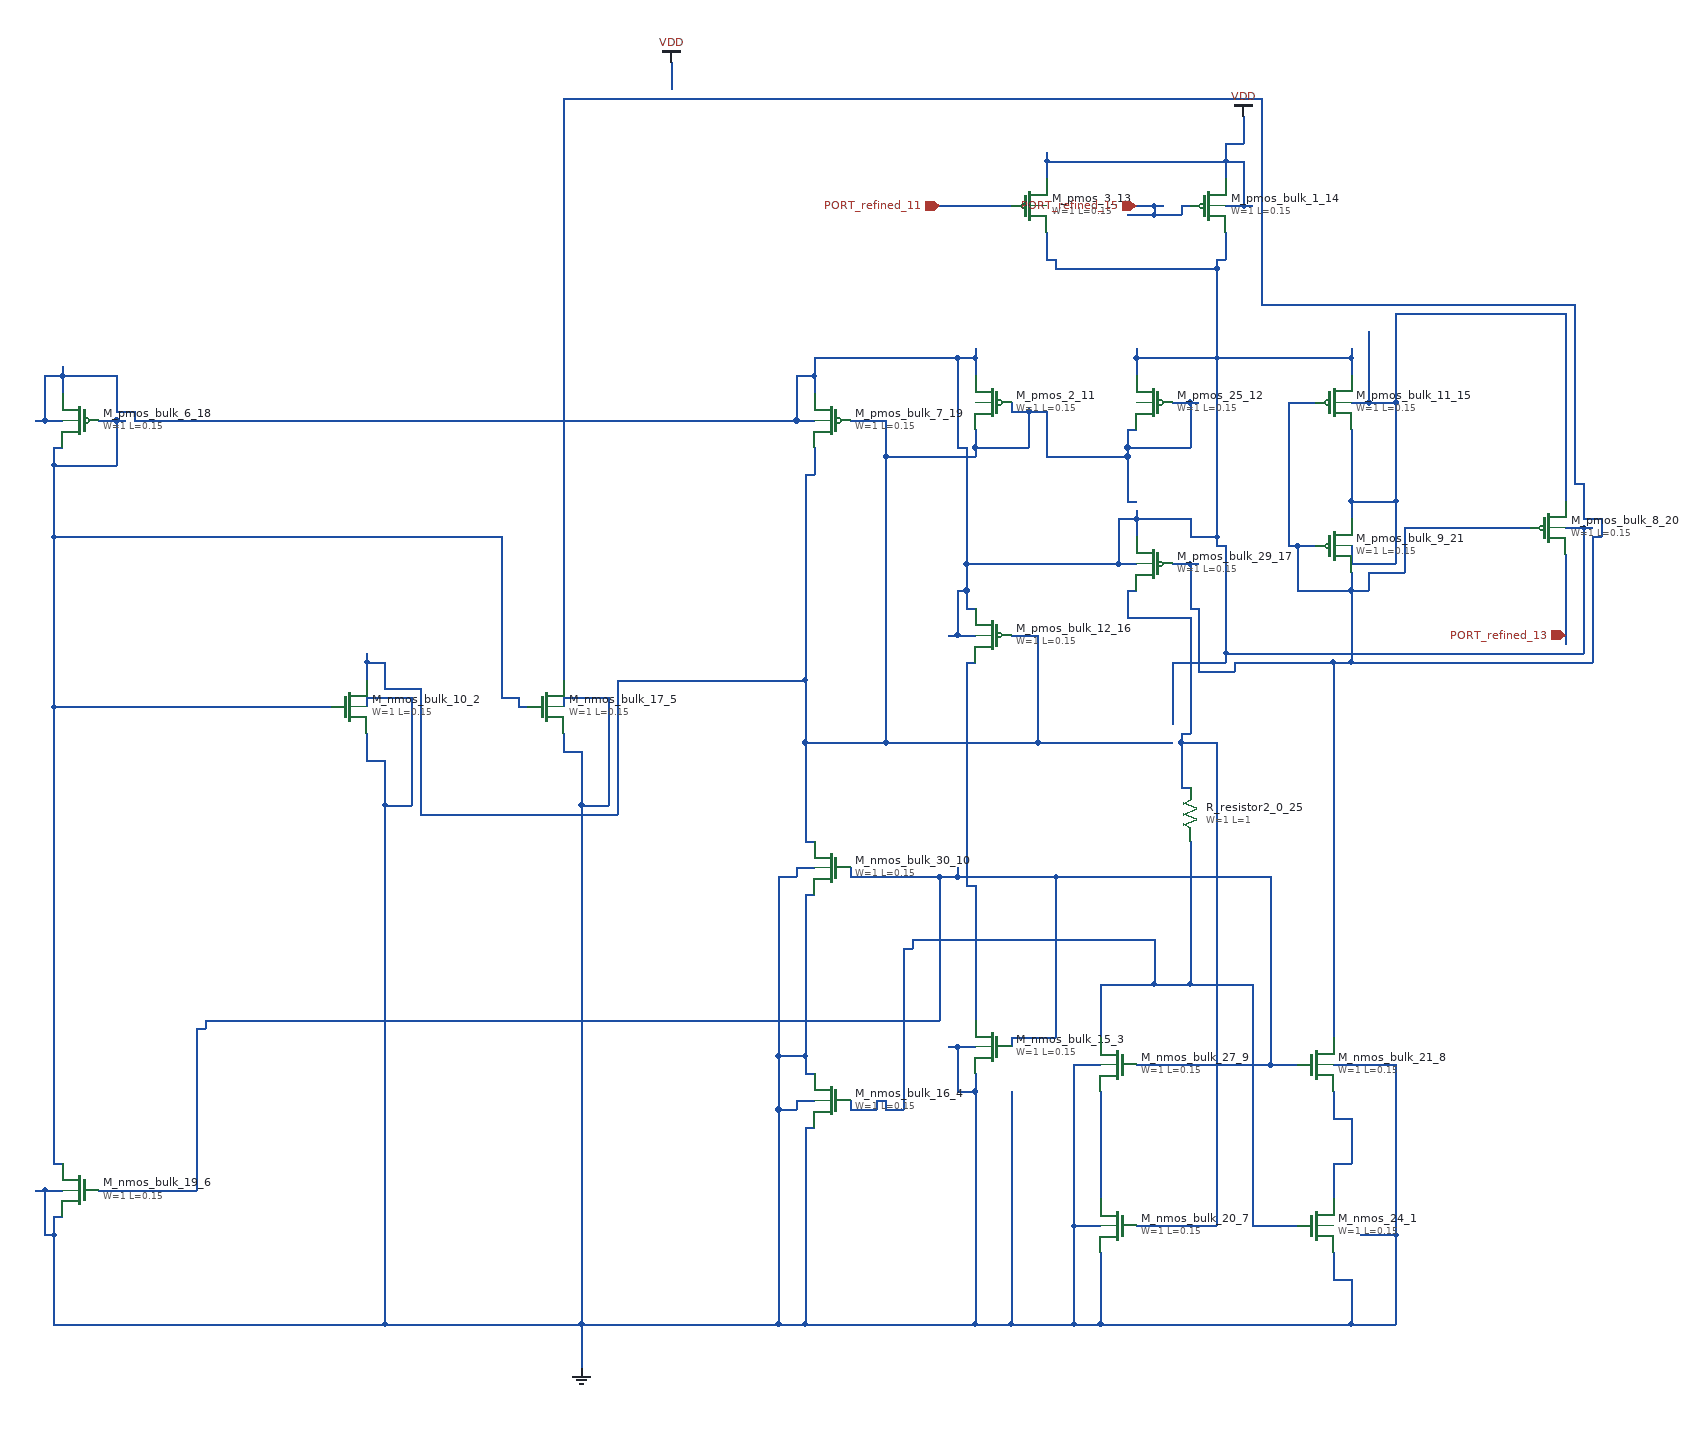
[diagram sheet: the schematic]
v {xschem version=3.4.8 file_version=1.2}
G {}
K {}
V {}
S {}
E {}
C {devices/gnd.sym} 800 1540 0 0 {name="l_gnd_5_0" lab="GND"}
C {sky130_fd_pr/nfet3_01v8.sym} 1620 1380 0 0 {name="M_nmos_24_1"
W=1
L=0.15
body=GND
nf=1
mult=1
ad="expr('int((@nf + 1)/2) * @W / @nf * 0.29')"
pd="expr('2*int((@nf + 1)/2) * (@W / @nf + 0.29)')"
as="expr('int((@nf + 2)/2) * @W / @nf * 0.29')"
ps="expr('2*int((@nf + 2)/2) * (@W / @nf + 0.29)')"
nrd="expr('0.29 / @W ')" nrs="expr('0.29 / @W ')"
sa=0 sb=0 sd=0
model=nfet_01v8
spiceprefix=X
}
C {sky130_fd_pr/nfet_01v8.sym} 540 800 0 0 {name="M_nmos_bulk_10_2"
W=1
L=0.15
nf=1 
mult=1
ad="expr('int((@nf + 1)/2) * @W / @nf * 0.29')"
pd="expr('2*int((@nf + 1)/2) * (@W / @nf + 0.29)')"
as="expr('int((@nf + 2)/2) * @W / @nf * 0.29')"
ps="expr('2*int((@nf + 2)/2) * (@W / @nf + 0.29)')"
nrd="expr('0.29 / @W ')" nrs="expr('0.29 / @W ')"
sa=0 sb=0 sd=0
model=nfet_01v8
spiceprefix=X
}
C {sky130_fd_pr/nfet_01v8.sym} 1260 1180 0 1 {name="M_nmos_bulk_15_3"
W=1
L=0.15
nf=1 
mult=1
ad="expr('int((@nf + 1)/2) * @W / @nf * 0.29')"
pd="expr('2*int((@nf + 1)/2) * (@W / @nf + 0.29)')"
as="expr('int((@nf + 2)/2) * @W / @nf * 0.29')"
ps="expr('2*int((@nf + 2)/2) * (@W / @nf + 0.29)')"
nrd="expr('0.29 / @W ')" nrs="expr('0.29 / @W ')"
sa=0 sb=0 sd=0
model=nfet_01v8
spiceprefix=X
}
C {sky130_fd_pr/nfet_01v8.sym} 1080 1240 0 1 {name="M_nmos_bulk_16_4"
W=1
L=0.15
nf=1 
mult=1
ad="expr('int((@nf + 1)/2) * @W / @nf * 0.29')"
pd="expr('2*int((@nf + 1)/2) * (@W / @nf + 0.29)')"
as="expr('int((@nf + 2)/2) * @W / @nf * 0.29')"
ps="expr('2*int((@nf + 2)/2) * (@W / @nf + 0.29)')"
nrd="expr('0.29 / @W ')" nrs="expr('0.29 / @W ')"
sa=0 sb=0 sd=0
model=nfet_01v8
spiceprefix=X
}
C {sky130_fd_pr/nfet_01v8.sym} 760 800 0 0 {name="M_nmos_bulk_17_5"
W=1
L=0.15
nf=1 
mult=1
ad="expr('int((@nf + 1)/2) * @W / @nf * 0.29')"
pd="expr('2*int((@nf + 1)/2) * (@W / @nf + 0.29)')"
as="expr('int((@nf + 2)/2) * @W / @nf * 0.29')"
ps="expr('2*int((@nf + 2)/2) * (@W / @nf + 0.29)')"
nrd="expr('0.29 / @W ')" nrs="expr('0.29 / @W ')"
sa=0 sb=0 sd=0
model=nfet_01v8
spiceprefix=X
}
C {sky130_fd_pr/nfet_01v8.sym} 240 1340 0 1 {name="M_nmos_bulk_19_6"
W=1
L=0.15
nf=1 
mult=1
ad="expr('int((@nf + 1)/2) * @W / @nf * 0.29')"
pd="expr('2*int((@nf + 1)/2) * (@W / @nf + 0.29)')"
as="expr('int((@nf + 2)/2) * @W / @nf * 0.29')"
ps="expr('2*int((@nf + 2)/2) * (@W / @nf + 0.29)')"
nrd="expr('0.29 / @W ')" nrs="expr('0.29 / @W ')"
sa=0 sb=0 sd=0
model=nfet_01v8
spiceprefix=X
}
C {sky130_fd_pr/nfet_01v8.sym} 1400 1380 0 1 {name="M_nmos_bulk_20_7"
W=1
L=0.15
nf=1 
mult=1
ad="expr('int((@nf + 1)/2) * @W / @nf * 0.29')"
pd="expr('2*int((@nf + 1)/2) * (@W / @nf + 0.29)')"
as="expr('int((@nf + 2)/2) * @W / @nf * 0.29')"
ps="expr('2*int((@nf + 2)/2) * (@W / @nf + 0.29)')"
nrd="expr('0.29 / @W ')" nrs="expr('0.29 / @W ')"
sa=0 sb=0 sd=0
model=nfet_01v8
spiceprefix=X
}
C {sky130_fd_pr/nfet_01v8.sym} 1620 1200 0 0 {name="M_nmos_bulk_21_8"
W=1
L=0.15
nf=1 
mult=1
ad="expr('int((@nf + 1)/2) * @W / @nf * 0.29')"
pd="expr('2*int((@nf + 1)/2) * (@W / @nf + 0.29)')"
as="expr('int((@nf + 2)/2) * @W / @nf * 0.29')"
ps="expr('2*int((@nf + 2)/2) * (@W / @nf + 0.29)')"
nrd="expr('0.29 / @W ')" nrs="expr('0.29 / @W ')"
sa=0 sb=0 sd=0
model=nfet_01v8
spiceprefix=X
}
C {sky130_fd_pr/nfet_01v8.sym} 1400 1200 0 1 {name="M_nmos_bulk_27_9"
W=1
L=0.15
nf=1 
mult=1
ad="expr('int((@nf + 1)/2) * @W / @nf * 0.29')"
pd="expr('2*int((@nf + 1)/2) * (@W / @nf + 0.29)')"
as="expr('int((@nf + 2)/2) * @W / @nf * 0.29')"
ps="expr('2*int((@nf + 2)/2) * (@W / @nf + 0.29)')"
nrd="expr('0.29 / @W ')" nrs="expr('0.29 / @W ')"
sa=0 sb=0 sd=0
model=nfet_01v8
spiceprefix=X
}
C {sky130_fd_pr/nfet_01v8.sym} 1080 980 0 1 {name="M_nmos_bulk_30_10"
W=1
L=0.15
nf=1 
mult=1
ad="expr('int((@nf + 1)/2) * @W / @nf * 0.29')"
pd="expr('2*int((@nf + 1)/2) * (@W / @nf + 0.29)')"
as="expr('int((@nf + 2)/2) * @W / @nf * 0.29')"
ps="expr('2*int((@nf + 2)/2) * (@W / @nf + 0.29)')"
nrd="expr('0.29 / @W ')" nrs="expr('0.29 / @W ')"
sa=0 sb=0 sd=0
model=nfet_01v8
spiceprefix=X
}
C {sky130_fd_pr/pfet3_01v8.sym} 1260 460 0 1 {name="M_pmos_2_11"
W=1
L=0.15
body=VDD
nf=1
mult=1
ad="expr('int((@nf + 1)/2) * @W / @nf * 0.29')"
pd="expr('2*int((@nf + 1)/2) * (@W / @nf + 0.29)')"
as="expr('int((@nf + 2)/2) * @W / @nf * 0.29')"
ps="expr('2*int((@nf + 2)/2) * (@W / @nf + 0.29)')"
nrd="expr('0.29 / @W ')" nrs="expr('0.29 / @W ')"
sa=0 sb=0 sd=0
model=pfet_01v8
spiceprefix=X
}
C {sky130_fd_pr/pfet3_01v8.sym} 1440 460 0 1 {name="M_pmos_25_12"
W=1
L=0.15
body=VDD
nf=1
mult=1
ad="expr('int((@nf + 1)/2) * @W / @nf * 0.29')"
pd="expr('2*int((@nf + 1)/2) * (@W / @nf + 0.29)')"
as="expr('int((@nf + 2)/2) * @W / @nf * 0.29')"
ps="expr('2*int((@nf + 2)/2) * (@W / @nf + 0.29)')"
nrd="expr('0.29 / @W ')" nrs="expr('0.29 / @W ')"
sa=0 sb=0 sd=0
model=pfet_01v8
spiceprefix=X
}
C {sky130_fd_pr/pfet3_01v8.sym} 1300 240 0 0 {name="M_pmos_3_13"
W=1
L=0.15
body=VDD
nf=1
mult=1
ad="expr('int((@nf + 1)/2) * @W / @nf * 0.29')"
pd="expr('2*int((@nf + 1)/2) * (@W / @nf + 0.29)')"
as="expr('int((@nf + 2)/2) * @W / @nf * 0.29')"
ps="expr('2*int((@nf + 2)/2) * (@W / @nf + 0.29)')"
nrd="expr('0.29 / @W ')" nrs="expr('0.29 / @W ')"
sa=0 sb=0 sd=0
model=pfet_01v8
spiceprefix=X
}
C {sky130_fd_pr/pfet_01v8.sym} 1500 240 0 0 {name="M_pmos_bulk_1_14"
W=1
L=0.15
nf=1
mult=1
ad="expr('int((@nf + 1)/2) * @W / @nf * 0.29')"
pd="expr('2*int((@nf + 1)/2) * (@W / @nf + 0.29)')"
as="expr('int((@nf + 2)/2) * @W / @nf * 0.29')"
ps="expr('2*int((@nf + 2)/2) * (@W / @nf + 0.29)')"
nrd="expr('0.29 / @W ')" nrs="expr('0.29 / @W ')"
sa=0 sb=0 sd=0
model=pfet_01v8
spiceprefix=X
}
C {sky130_fd_pr/pfet_01v8.sym} 1640 460 0 0 {name="M_pmos_bulk_11_15"
W=1
L=0.15
nf=1
mult=1
ad="expr('int((@nf + 1)/2) * @W / @nf * 0.29')"
pd="expr('2*int((@nf + 1)/2) * (@W / @nf + 0.29)')"
as="expr('int((@nf + 2)/2) * @W / @nf * 0.29')"
ps="expr('2*int((@nf + 2)/2) * (@W / @nf + 0.29)')"
nrd="expr('0.29 / @W ')" nrs="expr('0.29 / @W ')"
sa=0 sb=0 sd=0
model=pfet_01v8
spiceprefix=X
}
C {sky130_fd_pr/pfet_01v8.sym} 1260 720 0 1 {name="M_pmos_bulk_12_16"
W=1
L=0.15
nf=1
mult=1
ad="expr('int((@nf + 1)/2) * @W / @nf * 0.29')"
pd="expr('2*int((@nf + 1)/2) * (@W / @nf + 0.29)')"
as="expr('int((@nf + 2)/2) * @W / @nf * 0.29')"
ps="expr('2*int((@nf + 2)/2) * (@W / @nf + 0.29)')"
nrd="expr('0.29 / @W ')" nrs="expr('0.29 / @W ')"
sa=0 sb=0 sd=0
model=pfet_01v8
spiceprefix=X
}
C {sky130_fd_pr/pfet_01v8.sym} 1440 640 0 1 {name="M_pmos_bulk_29_17"
W=1
L=0.15
nf=1
mult=1
ad="expr('int((@nf + 1)/2) * @W / @nf * 0.29')"
pd="expr('2*int((@nf + 1)/2) * (@W / @nf + 0.29)')"
as="expr('int((@nf + 2)/2) * @W / @nf * 0.29')"
ps="expr('2*int((@nf + 2)/2) * (@W / @nf + 0.29)')"
nrd="expr('0.29 / @W ')" nrs="expr('0.29 / @W ')"
sa=0 sb=0 sd=0
model=pfet_01v8
spiceprefix=X
}
C {sky130_fd_pr/pfet_01v8.sym} 240 480 0 1 {name="M_pmos_bulk_6_18"
W=1
L=0.15
nf=1
mult=1
ad="expr('int((@nf + 1)/2) * @W / @nf * 0.29')"
pd="expr('2*int((@nf + 1)/2) * (@W / @nf + 0.29)')"
as="expr('int((@nf + 2)/2) * @W / @nf * 0.29')"
ps="expr('2*int((@nf + 2)/2) * (@W / @nf + 0.29)')"
nrd="expr('0.29 / @W ')" nrs="expr('0.29 / @W ')"
sa=0 sb=0 sd=0
model=pfet_01v8
spiceprefix=X
}
C {sky130_fd_pr/pfet_01v8.sym} 1080 480 0 1 {name="M_pmos_bulk_7_19"
W=1
L=0.15
nf=1
mult=1
ad="expr('int((@nf + 1)/2) * @W / @nf * 0.29')"
pd="expr('2*int((@nf + 1)/2) * (@W / @nf + 0.29)')"
as="expr('int((@nf + 2)/2) * @W / @nf * 0.29')"
ps="expr('2*int((@nf + 2)/2) * (@W / @nf + 0.29)')"
nrd="expr('0.29 / @W ')" nrs="expr('0.29 / @W ')"
sa=0 sb=0 sd=0
model=pfet_01v8
spiceprefix=X
}
C {sky130_fd_pr/pfet_01v8.sym} 1880 600 0 0 {name="M_pmos_bulk_8_20"
W=1
L=0.15
nf=1
mult=1
ad="expr('int((@nf + 1)/2) * @W / @nf * 0.29')"
pd="expr('2*int((@nf + 1)/2) * (@W / @nf + 0.29)')"
as="expr('int((@nf + 2)/2) * @W / @nf * 0.29')"
ps="expr('2*int((@nf + 2)/2) * (@W / @nf + 0.29)')"
nrd="expr('0.29 / @W ')" nrs="expr('0.29 / @W ')"
sa=0 sb=0 sd=0
model=pfet_01v8
spiceprefix=X
}
C {sky130_fd_pr/pfet_01v8.sym} 1640 620 0 0 {name="M_pmos_bulk_9_21"
W=1
L=0.15
nf=1
mult=1
ad="expr('int((@nf + 1)/2) * @W / @nf * 0.29')"
pd="expr('2*int((@nf + 1)/2) * (@W / @nf + 0.29)')"
as="expr('int((@nf + 2)/2) * @W / @nf * 0.29')"
ps="expr('2*int((@nf + 2)/2) * (@W / @nf + 0.29)')"
nrd="expr('0.29 / @W ')" nrs="expr('0.29 / @W ')"
sa=0 sb=0 sd=0
model=pfet_01v8
spiceprefix=X
}
C {devices/ipin.sym} 1200 240 0 0 {name="p_port_39_22" lab="PORT_refined_11"}
C {devices/ipin.sym} 1900 720 0 0 {name="p_port_4_23" lab="PORT_refined_13"}
C {devices/ipin.sym} 1420 240 0 0 {name="p_port_40_24" lab="PORT_refined_15"}
C {sky130_fd_pr/res_generic_po.sym} 1480 920 2 0 {name="R_resistor2_0_25"
W=1
L=1
model=res_generic_po
spiceprefix=X
mult=1}
C {devices/vdd.sym} 900 80 0 0 {name="l_vdd_14_26" lab="VDD"}
C {devices/vdd.sym} 1540 140 0 0 {name="l_vdd_23_27" lab="VDD"}
N 210 1490 580 1490 {}
N 580 1490 800 1490 {}
N 800 1490 1020 1490 {}
N 1020 1490 1050 1490 {}
N 1050 1490 1240 1490 {}
N 1240 1490 1280 1490 {}
N 1280 1490 1350 1490 {}
N 1350 1490 1380 1490 {}
N 1380 1490 1660 1490 {}
N 1660 1490 1710 1490 {}
N 1640 1440 1660 1440 {}
N 200 1390 210 1390 {}
N 1670 1390 1710 1390 {}
N 1350 1380 1380 1380 {}
N 210 1370 220 1370 {}
N 190 1340 200 1340 {}
N 200 1340 220 1340 {}
N 1050 1270 1060 1270 {}
N 1020 1250 1040 1250 {}
N 1040 1240 1060 1240 {}
N 1220 1230 1240 1230 {}
N 1050 1210 1060 1210 {}
N 1350 1200 1380 1200 {}
N 1640 1200 1710 1200 {}
N 1020 1190 1050 1190 {}
N 1210 1180 1220 1180 {}
N 1220 1180 1240 1180 {}
N 1050 1010 1060 1010 {}
N 1020 990 1040 990 {}
N 1040 980 1060 980 {}
N 580 910 610 910 {}
N 800 910 830 910 {}
N 560 860 580 860 {}
N 780 850 800 850 {}
N 560 790 610 790 {}
N 780 790 830 790 {}
N 200 1390 200 1340 {}
N 210 1490 210 1390 {}
N 210 1390 210 1370 {}
N 560 860 560 830 {}
N 560 800 560 790 {}
N 580 1490 580 910 {}
N 580 910 580 860 {}
N 610 910 610 790 {}
N 780 850 780 830 {}
N 780 800 780 790 {}
N 800 1540 800 1490 {}
N 800 1490 800 910 {}
N 800 910 800 850 {}
N 830 910 830 790 {}
N 1020 1490 1020 1250 {}
N 1020 1250 1020 1190 {}
N 1020 1190 1020 990 {}
N 1040 1250 1040 1240 {}
N 1040 990 1040 980 {}
N 1050 1490 1050 1270 {}
N 1050 1210 1050 1190 {}
N 1050 1190 1050 1010 {}
N 1220 1230 1220 1180 {}
N 1240 1490 1240 1230 {}
N 1240 1230 1240 1210 {}
N 1280 1490 1280 1230 {}
N 1350 1490 1350 1380 {}
N 1350 1380 1350 1200 {}
N 1380 1490 1380 1410 {}
N 1640 1440 1640 1410 {}
N 1660 1490 1660 1440 {}
N 1710 1490 1710 1390 {}
N 1710 1390 1710 1200 {}
N 1640 1310 1660 1310 {}
N 1640 1260 1660 1260 {}
N 1640 1350 1640 1310 {}
N 1640 1260 1640 1230 {}
N 1660 1310 1660 1260 {}
N 1520 240 1540 240 {}
N 1540 240 1550 240 {}
N 1320 190 1520 190 {}
N 1520 190 1540 190 {}
N 1520 170 1540 170 {}
N 900 110 900 80 {}
N 1320 210 1320 190 {}
N 1320 190 1320 180 {}
N 1520 210 1520 190 {}
N 1520 190 1520 170 {}
N 1540 240 1540 190 {}
N 1540 170 1540 140 {}
N 1200 240 1280 240 {}
N 1660 640 1710 640 {}
N 1660 570 1710 570 {}
N 1660 460 1680 460 {}
N 1680 460 1710 460 {}
N 1710 360 1900 360 {}
N 1660 640 1660 620 {}
N 1660 590 1660 570 {}
N 1660 570 1660 490 {}
N 1680 460 1680 380 {}
N 1710 640 1710 570 {}
N 1710 570 1710 460 {}
N 1710 460 1710 360 {}
N 1900 570 1900 360 {}
N 1900 730 1900 720 {}
N 1900 720 1900 630 {}
N 1460 750 1520 750 {}
N 1520 740 1920 740 {}
N 1210 720 1220 720 {}
N 1220 720 1240 720 {}
N 1230 690 1240 690 {}
N 1220 670 1230 670 {}
N 1230 640 1400 640 {}
N 1400 640 1420 640 {}
N 1510 620 1520 620 {}
N 1480 610 1510 610 {}
N 1900 600 1920 600 {}
N 1920 600 1930 600 {}
N 1400 590 1420 590 {}
N 1420 590 1480 590 {}
N 1220 510 1230 510 {}
N 190 480 200 480 {}
N 200 480 220 480 {}
N 300 480 1040 480 {}
N 1040 480 1060 480 {}
N 280 470 300 470 {}
N 200 430 220 430 {}
N 220 430 280 430 {}
N 1040 430 1060 430 {}
N 1060 410 1220 410 {}
N 1220 410 1240 410 {}
N 1420 410 1510 410 {}
N 1510 410 1660 410 {}
N 1330 310 1510 310 {}
N 1320 300 1330 300 {}
N 1510 300 1520 300 {}
N 200 480 200 430 {}
N 220 450 220 430 {}
N 220 430 220 420 {}
N 280 470 280 430 {}
N 300 480 300 470 {}
N 1040 480 1040 430 {}
N 1060 450 1060 430 {}
N 1060 430 1060 410 {}
N 1220 720 1220 670 {}
N 1220 510 1220 410 {}
N 1230 690 1230 670 {}
N 1230 670 1230 640 {}
N 1230 640 1230 510 {}
N 1240 430 1240 410 {}
N 1240 410 1240 400 {}
N 1320 300 1320 270 {}
N 1330 310 1330 300 {}
N 1400 640 1400 590 {}
N 1420 610 1420 590 {}
N 1420 590 1420 580 {}
N 1420 430 1420 410 {}
N 1420 410 1420 400 {}
N 1460 820 1460 750 {}
N 1480 610 1480 590 {}
N 1510 620 1510 610 {}
N 1510 610 1510 410 {}
N 1510 410 1510 310 {}
N 1510 310 1510 300 {}
N 1520 750 1520 740 {}
N 1520 740 1520 620 {}
N 1520 300 1520 270 {}
N 1660 430 1660 410 {}
N 1660 410 1660 400 {}
N 1920 740 1920 600 {}
N 1410 250 1440 250 {}
N 1440 250 1470 250 {}
N 1420 240 1440 240 {}
N 1440 240 1450 240 {}
N 1470 240 1480 240 {}
N 1440 250 1440 240 {}
N 1470 250 1470 240 {}
N 1230 1000 1240 1000 {}
N 1230 750 1240 750 {}
N 1230 1000 1230 750 {}
N 1240 1150 1240 1000 {}
N 260 1340 370 1340 {}
N 1420 1200 1570 1200 {}
N 1570 1200 1600 1200 {}
N 1280 1170 1330 1170 {}
N 370 1160 380 1160 {}
N 380 1150 1200 1150 {}
N 1100 990 1200 990 {}
N 1200 990 1220 990 {}
N 1220 990 1330 990 {}
N 1330 990 1570 990 {}
N 370 1340 370 1160 {}
N 380 1160 380 1150 {}
N 1100 990 1100 980 {}
N 1200 1150 1200 990 {}
N 1220 990 1220 980 {}
N 1280 1180 1280 1170 {}
N 1330 1170 1330 990 {}
N 1570 1200 1570 990 {}
N 1550 1380 1600 1380 {}
N 1100 1250 1130 1250 {}
N 1140 1250 1160 1250 {}
N 1130 1240 1140 1240 {}
N 1380 1110 1440 1110 {}
N 1440 1110 1480 1110 {}
N 1480 1110 1550 1110 {}
N 1160 1070 1170 1070 {}
N 1170 1060 1440 1060 {}
N 1100 1250 1100 1240 {}
N 1130 1250 1130 1240 {}
N 1140 1250 1140 1240 {}
N 1160 1250 1160 1070 {}
N 1170 1070 1170 1060 {}
N 1380 1170 1380 1110 {}
N 1440 1110 1440 1060 {}
N 1480 1110 1480 950 {}
N 1550 1380 1550 1110 {}
N 1490 760 1530 760 {}
N 1530 750 1640 750 {}
N 1640 750 1660 750 {}
N 1660 750 1930 750 {}
N 1480 690 1490 690 {}
N 1600 670 1660 670 {}
N 1660 670 1680 670 {}
N 1680 650 1720 650 {}
N 1460 640 1480 640 {}
N 1480 640 1490 640 {}
N 1590 620 1600 620 {}
N 1600 620 1620 620 {}
N 1930 610 1940 610 {}
N 1720 600 1860 600 {}
N 1920 590 1940 590 {}
N 1910 550 1920 550 {}
N 1590 460 1620 460 {}
N 1560 350 1910 350 {}
N 780 120 1560 120 {}
N 780 770 780 120 {}
N 1480 690 1480 640 {}
N 1490 760 1490 690 {}
N 1530 760 1530 750 {}
N 1560 350 1560 120 {}
N 1590 620 1590 460 {}
N 1600 670 1600 620 {}
N 1640 1170 1640 750 {}
N 1660 750 1660 670 {}
N 1660 670 1660 650 {}
N 1680 670 1680 650 {}
N 1720 650 1720 600 {}
N 1910 550 1910 350 {}
N 1920 590 1920 550 {}
N 1930 750 1930 610 {}
N 1940 610 1940 590 {}
N 210 1310 220 1310 {}
N 210 800 520 800 {}
N 730 800 740 800 {}
N 710 790 730 790 {}
N 210 610 710 610 {}
N 210 530 280 530 {}
N 210 510 220 510 {}
N 260 480 280 480 {}
N 280 480 290 480 {}
N 210 1310 210 800 {}
N 210 800 210 610 {}
N 210 610 210 530 {}
N 210 530 210 510 {}
N 280 530 280 480 {}
N 710 790 710 610 {}
N 730 800 730 790 {}
N 1380 1350 1380 1230 {}
N 1420 1380 1510 1380 {}
N 1470 890 1480 890 {}
N 1470 840 1510 840 {}
N 1470 830 1480 830 {}
N 1410 700 1480 700 {}
N 1410 670 1420 670 {}
N 1410 700 1410 670 {}
N 1470 890 1470 840 {}
N 1470 840 1470 830 {}
N 1480 830 1480 700 {}
N 1510 1380 1510 840 {}
N 1050 950 1060 950 {}
N 620 920 840 920 {}
N 1050 840 1140 840 {}
N 1140 840 1310 840 {}
N 1310 840 1460 840 {}
N 580 780 620 780 {}
N 840 770 1050 770 {}
N 560 750 580 750 {}
N 1280 720 1310 720 {}
N 1410 570 1420 570 {}
N 1050 540 1060 540 {}
N 1140 520 1240 520 {}
N 1320 520 1410 520 {}
N 1240 510 1300 510 {}
N 1410 510 1480 510 {}
N 1410 490 1420 490 {}
N 1100 480 1140 480 {}
N 1280 470 1300 470 {}
N 1300 470 1320 470 {}
N 1460 460 1480 460 {}
N 1480 460 1490 460 {}
N 560 770 560 750 {}
N 560 750 560 740 {}
N 580 780 580 750 {}
N 620 920 620 780 {}
N 840 920 840 770 {}
N 1050 950 1050 840 {}
N 1050 840 1050 770 {}
N 1050 770 1050 540 {}
N 1060 540 1060 510 {}
N 1140 840 1140 520 {}
N 1140 520 1140 480 {}
N 1240 520 1240 510 {}
N 1240 510 1240 490 {}
N 1280 470 1280 460 {}
N 1300 510 1300 470 {}
N 1310 840 1310 720 {}
N 1320 520 1320 470 {}
N 1410 570 1410 520 {}
N 1410 520 1410 510 {}
N 1410 510 1410 490 {}
N 1480 510 1480 460 {}
